One B-rep face of a CAD part: STEP entity #162.
In plain terms, the planar face has unit normal (1, 0, 0).
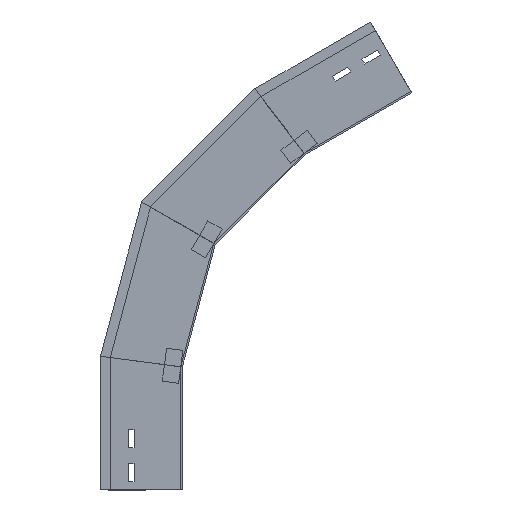
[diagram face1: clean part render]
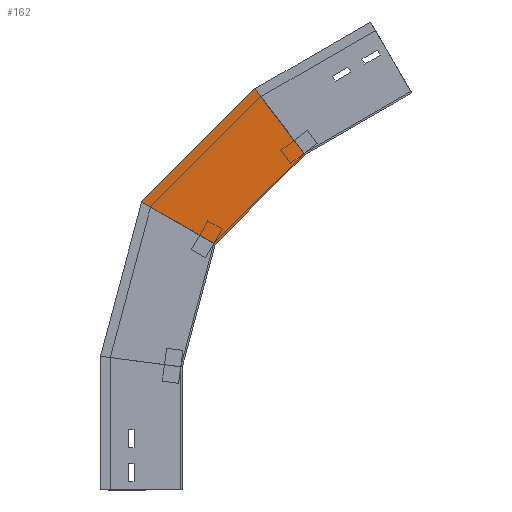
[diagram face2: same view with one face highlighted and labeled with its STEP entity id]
Its self-contained STEP definition (entity closure, numbers rounded to 3 decimals):
#6 = VERTEX_POINT ( 'NONE', #1630 ) ;
#9 = LINE ( 'NONE', #934, #876 ) ;
#96 = ORIENTED_EDGE ( 'NONE', *, *, #931, .F. ) ;
#106 = EDGE_CURVE ( 'NONE', #998, #1490, #654, .T. ) ;
#121 = DIRECTION ( 'NONE',  ( 0., -0.259, 0.966 ) ) ;
#126 = EDGE_CURVE ( 'NONE', #998, #1310, #9, .T. ) ;
#162 = ADVANCED_FACE ( 'NONE', ( #1401 ), #1274, .T. ) ;
#187 = CARTESIAN_POINT ( 'NONE',  ( 0., 49.541, 351.482 ) ) ;
#252 = ORIENTED_EDGE ( 'NONE', *, *, #126, .T. ) ;
#261 = DIRECTION ( 'NONE',  ( 0., -0.259, 0.966 ) ) ;
#323 = LINE ( 'NONE', #603, #487 ) ;
#371 = VECTOR ( 'NONE', #1656, 1000. ) ;
#415 = CARTESIAN_POINT ( 'NONE',  ( 0., 3.774, 135.915 ) ) ;
#487 = VECTOR ( 'NONE', #894, 1000. ) ;
#583 = ORIENTED_EDGE ( 'NONE', *, *, #618, .T. ) ;
#603 = CARTESIAN_POINT ( 'NONE',  ( 0., -78.128, 277.773 ) ) ;
#611 = ORIENTED_EDGE ( 'NONE', *, *, #106, .F. ) ;
#618 = EDGE_CURVE ( 'NONE', #1310, #6, #323, .T. ) ;
#645 = CARTESIAN_POINT ( 'NONE',  ( 0., -19.411, 147.444 ) ) ;
#654 = LINE ( 'NONE', #645, #371 ) ;
#715 = CARTESIAN_POINT ( 'NONE',  ( 0., 100., 163.165 ) ) ;
#736 = AXIS2_PLACEMENT_3D ( 'NONE', #415, #1573, #1136 ) ;
#784 = LINE ( 'NONE', #1416, #1562 ) ;
#876 = VECTOR ( 'NONE', #121, 1000. ) ;
#894 = DIRECTION ( 'NONE',  ( 0., -0.866, -0.5 ) ) ;
#931 = EDGE_CURVE ( 'NONE', #1490, #6, #784, .T. ) ;
#934 = CARTESIAN_POINT ( 'NONE',  ( 0., 100.367, 161.797 ) ) ;
#978 = EDGE_LOOP ( 'NONE', ( #252, #583, #96, #611 ) ) ;
#998 = VERTEX_POINT ( 'NONE', #715 ) ;
#1136 = DIRECTION ( 'NONE',  ( 0., 0., -1. ) ) ;
#1274 = PLANE ( 'NONE',  #736 ) ;
#1310 = VERTEX_POINT ( 'NONE', #187 ) ;
#1401 = FACE_OUTER_BOUND ( 'NONE', #978, .T. ) ;
#1416 = CARTESIAN_POINT ( 'NONE',  ( 0., 3.774, 135.915 ) ) ;
#1490 = VERTEX_POINT ( 'NONE', #1535 ) ;
#1535 = CARTESIAN_POINT ( 'NONE',  ( 0., 0., 150. ) ) ;
#1562 = VECTOR ( 'NONE', #261, 1000. ) ;
#1573 = DIRECTION ( 'NONE',  ( 1., 0., 0. ) ) ;
#1630 = CARTESIAN_POINT ( 'NONE',  ( 0., -40.117, 299.719 ) ) ;
#1656 = DIRECTION ( 'NONE',  ( 0., -0.991, -0.131 ) ) ;
